VERSION 5.8 ;
BUSBITCHARS "[]" ;
DIVIDERCHAR "/" ;
UNITS
    DATABASE MICRONS 2000 ;
END UNITS

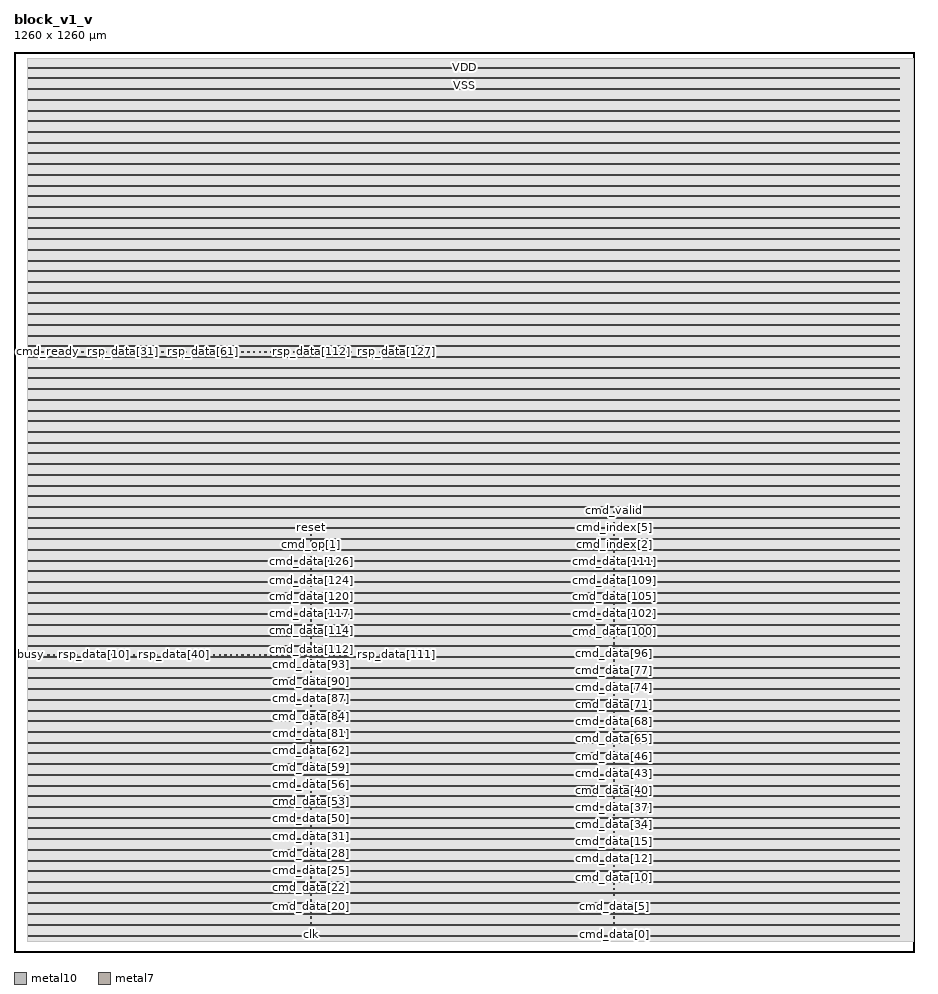
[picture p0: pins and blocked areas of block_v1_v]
MACRO block_v1_v
  FOREIGN block_v1_v 0 0 ;
  CLASS BLOCK ;
  SIZE 1260 BY 1260 ;
  PIN busy
    DIRECTION OUTPUT ;
    USE SIGNAL ;
    PORT
      LAYER metal10 ;
        RECT  23.095 415.07 25.095 417.07 ;
    END
  END busy
  PIN clk
    DIRECTION INPUT ;
    USE SIGNAL ;
    PORT
      LAYER metal10 ;
        RECT  415.095 23.07 417.095 25.07 ;
    END
  END clk
  PIN cmd_data[0]
    DIRECTION INPUT ;
    USE SIGNAL ;
    PORT
      LAYER metal10 ;
        RECT  839.095 23.07 841.095 25.07 ;
    END
  END cmd_data[0]
  PIN cmd_data[100]
    DIRECTION INPUT ;
    USE SIGNAL ;
    PORT
      LAYER metal10 ;
        RECT  839.095 447.07 841.095 449.07 ;
    END
  END cmd_data[100]
  PIN cmd_data[101]
    DIRECTION INPUT ;
    USE SIGNAL ;
    PORT
      LAYER metal10 ;
        RECT  839.095 455.07 841.095 457.07 ;
    END
  END cmd_data[101]
  PIN cmd_data[102]
    DIRECTION INPUT ;
    USE SIGNAL ;
    PORT
      LAYER metal10 ;
        RECT  839.095 463.07 841.095 465.07 ;
    END
  END cmd_data[102]
  PIN cmd_data[103]
    DIRECTION INPUT ;
    USE SIGNAL ;
    PORT
      LAYER metal10 ;
        RECT  839.095 471.07 841.095 473.07 ;
    END
  END cmd_data[103]
  PIN cmd_data[104]
    DIRECTION INPUT ;
    USE SIGNAL ;
    PORT
      LAYER metal10 ;
        RECT  839.095 479.07 841.095 481.07 ;
    END
  END cmd_data[104]
  PIN cmd_data[105]
    DIRECTION INPUT ;
    USE SIGNAL ;
    PORT
      LAYER metal10 ;
        RECT  839.095 487.07 841.095 489.07 ;
    END
  END cmd_data[105]
  PIN cmd_data[106]
    DIRECTION INPUT ;
    USE SIGNAL ;
    PORT
      LAYER metal10 ;
        RECT  839.095 495.07 841.095 497.07 ;
    END
  END cmd_data[106]
  PIN cmd_data[107]
    DIRECTION INPUT ;
    USE SIGNAL ;
    PORT
      LAYER metal10 ;
        RECT  839.095 503.07 841.095 505.07 ;
    END
  END cmd_data[107]
  PIN cmd_data[108]
    DIRECTION INPUT ;
    USE SIGNAL ;
    PORT
      LAYER metal10 ;
        RECT  839.095 511.07 841.095 513.07 ;
    END
  END cmd_data[108]
  PIN cmd_data[109]
    DIRECTION INPUT ;
    USE SIGNAL ;
    PORT
      LAYER metal10 ;
        RECT  839.095 519.07 841.095 521.07 ;
    END
  END cmd_data[109]
  PIN cmd_data[10]
    DIRECTION INPUT ;
    USE SIGNAL ;
    PORT
      LAYER metal10 ;
        RECT  839.095 103.07 841.095 105.07 ;
    END
  END cmd_data[10]
  PIN cmd_data[110]
    DIRECTION INPUT ;
    USE SIGNAL ;
    PORT
      LAYER metal10 ;
        RECT  839.095 527.07 841.095 529.07 ;
    END
  END cmd_data[110]
  PIN cmd_data[111]
    DIRECTION INPUT ;
    USE SIGNAL ;
    PORT
      LAYER metal10 ;
        RECT  839.095 535.07 841.095 537.07 ;
    END
  END cmd_data[111]
  PIN cmd_data[112]
    DIRECTION INPUT ;
    USE SIGNAL ;
    PORT
      LAYER metal10 ;
        RECT  415.095 423.07 417.095 425.07 ;
    END
  END cmd_data[112]
  PIN cmd_data[113]
    DIRECTION INPUT ;
    USE SIGNAL ;
    PORT
      LAYER metal10 ;
        RECT  415.095 431.07 417.095 433.07 ;
    END
  END cmd_data[113]
  PIN cmd_data[114]
    DIRECTION INPUT ;
    USE SIGNAL ;
    PORT
      LAYER metal10 ;
        RECT  415.095 439.07 417.095 441.07 ;
    END
  END cmd_data[114]
  PIN cmd_data[115]
    DIRECTION INPUT ;
    USE SIGNAL ;
    PORT
      LAYER metal10 ;
        RECT  415.095 447.07 417.095 449.07 ;
    END
  END cmd_data[115]
  PIN cmd_data[116]
    DIRECTION INPUT ;
    USE SIGNAL ;
    PORT
      LAYER metal10 ;
        RECT  415.095 455.07 417.095 457.07 ;
    END
  END cmd_data[116]
  PIN cmd_data[117]
    DIRECTION INPUT ;
    USE SIGNAL ;
    PORT
      LAYER metal10 ;
        RECT  415.095 463.07 417.095 465.07 ;
    END
  END cmd_data[117]
  PIN cmd_data[118]
    DIRECTION INPUT ;
    USE SIGNAL ;
    PORT
      LAYER metal10 ;
        RECT  415.095 471.07 417.095 473.07 ;
    END
  END cmd_data[118]
  PIN cmd_data[119]
    DIRECTION INPUT ;
    USE SIGNAL ;
    PORT
      LAYER metal10 ;
        RECT  415.095 479.07 417.095 481.07 ;
    END
  END cmd_data[119]
  PIN cmd_data[11]
    DIRECTION INPUT ;
    USE SIGNAL ;
    PORT
      LAYER metal10 ;
        RECT  839.095 111.07 841.095 113.07 ;
    END
  END cmd_data[11]
  PIN cmd_data[120]
    DIRECTION INPUT ;
    USE SIGNAL ;
    PORT
      LAYER metal10 ;
        RECT  415.095 487.07 417.095 489.07 ;
    END
  END cmd_data[120]
  PIN cmd_data[121]
    DIRECTION INPUT ;
    USE SIGNAL ;
    PORT
      LAYER metal10 ;
        RECT  415.095 495.07 417.095 497.07 ;
    END
  END cmd_data[121]
  PIN cmd_data[122]
    DIRECTION INPUT ;
    USE SIGNAL ;
    PORT
      LAYER metal10 ;
        RECT  415.095 503.07 417.095 505.07 ;
    END
  END cmd_data[122]
  PIN cmd_data[123]
    DIRECTION INPUT ;
    USE SIGNAL ;
    PORT
      LAYER metal10 ;
        RECT  415.095 511.07 417.095 513.07 ;
    END
  END cmd_data[123]
  PIN cmd_data[124]
    DIRECTION INPUT ;
    USE SIGNAL ;
    PORT
      LAYER metal10 ;
        RECT  415.095 519.07 417.095 521.07 ;
    END
  END cmd_data[124]
  PIN cmd_data[125]
    DIRECTION INPUT ;
    USE SIGNAL ;
    PORT
      LAYER metal10 ;
        RECT  415.095 527.07 417.095 529.07 ;
    END
  END cmd_data[125]
  PIN cmd_data[126]
    DIRECTION INPUT ;
    USE SIGNAL ;
    PORT
      LAYER metal10 ;
        RECT  415.095 535.07 417.095 537.07 ;
    END
  END cmd_data[126]
  PIN cmd_data[127]
    DIRECTION INPUT ;
    USE SIGNAL ;
    PORT
      LAYER metal10 ;
        RECT  415.095 543.07 417.095 545.07 ;
    END
  END cmd_data[127]
  PIN cmd_data[12]
    DIRECTION INPUT ;
    USE SIGNAL ;
    PORT
      LAYER metal10 ;
        RECT  839.095 119.07 841.095 121.07 ;
    END
  END cmd_data[12]
  PIN cmd_data[13]
    DIRECTION INPUT ;
    USE SIGNAL ;
    PORT
      LAYER metal10 ;
        RECT  839.095 127.07 841.095 129.07 ;
    END
  END cmd_data[13]
  PIN cmd_data[14]
    DIRECTION INPUT ;
    USE SIGNAL ;
    PORT
      LAYER metal10 ;
        RECT  839.095 135.07 841.095 137.07 ;
    END
  END cmd_data[14]
  PIN cmd_data[15]
    DIRECTION INPUT ;
    USE SIGNAL ;
    PORT
      LAYER metal10 ;
        RECT  839.095 143.07 841.095 145.07 ;
    END
  END cmd_data[15]
  PIN cmd_data[16]
    DIRECTION INPUT ;
    USE SIGNAL ;
    PORT
      LAYER metal10 ;
        RECT  415.095 31.07 417.095 33.07 ;
    END
  END cmd_data[16]
  PIN cmd_data[17]
    DIRECTION INPUT ;
    USE SIGNAL ;
    PORT
      LAYER metal10 ;
        RECT  415.095 39.07 417.095 41.07 ;
    END
  END cmd_data[17]
  PIN cmd_data[18]
    DIRECTION INPUT ;
    USE SIGNAL ;
    PORT
      LAYER metal10 ;
        RECT  415.095 47.07 417.095 49.07 ;
    END
  END cmd_data[18]
  PIN cmd_data[19]
    DIRECTION INPUT ;
    USE SIGNAL ;
    PORT
      LAYER metal10 ;
        RECT  415.095 55.07 417.095 57.07 ;
    END
  END cmd_data[19]
  PIN cmd_data[1]
    DIRECTION INPUT ;
    USE SIGNAL ;
    PORT
      LAYER metal10 ;
        RECT  839.095 31.07 841.095 33.07 ;
    END
  END cmd_data[1]
  PIN cmd_data[20]
    DIRECTION INPUT ;
    USE SIGNAL ;
    PORT
      LAYER metal10 ;
        RECT  415.095 63.07 417.095 65.07 ;
    END
  END cmd_data[20]
  PIN cmd_data[21]
    DIRECTION INPUT ;
    USE SIGNAL ;
    PORT
      LAYER metal10 ;
        RECT  415.095 71.07 417.095 73.07 ;
    END
  END cmd_data[21]
  PIN cmd_data[22]
    DIRECTION INPUT ;
    USE SIGNAL ;
    PORT
      LAYER metal10 ;
        RECT  415.095 79.07 417.095 81.07 ;
    END
  END cmd_data[22]
  PIN cmd_data[23]
    DIRECTION INPUT ;
    USE SIGNAL ;
    PORT
      LAYER metal10 ;
        RECT  415.095 87.07 417.095 89.07 ;
    END
  END cmd_data[23]
  PIN cmd_data[24]
    DIRECTION INPUT ;
    USE SIGNAL ;
    PORT
      LAYER metal10 ;
        RECT  415.095 95.07 417.095 97.07 ;
    END
  END cmd_data[24]
  PIN cmd_data[25]
    DIRECTION INPUT ;
    USE SIGNAL ;
    PORT
      LAYER metal10 ;
        RECT  415.095 103.07 417.095 105.07 ;
    END
  END cmd_data[25]
  PIN cmd_data[26]
    DIRECTION INPUT ;
    USE SIGNAL ;
    PORT
      LAYER metal10 ;
        RECT  415.095 111.07 417.095 113.07 ;
    END
  END cmd_data[26]
  PIN cmd_data[27]
    DIRECTION INPUT ;
    USE SIGNAL ;
    PORT
      LAYER metal10 ;
        RECT  415.095 119.07 417.095 121.07 ;
    END
  END cmd_data[27]
  PIN cmd_data[28]
    DIRECTION INPUT ;
    USE SIGNAL ;
    PORT
      LAYER metal10 ;
        RECT  415.095 127.07 417.095 129.07 ;
    END
  END cmd_data[28]
  PIN cmd_data[29]
    DIRECTION INPUT ;
    USE SIGNAL ;
    PORT
      LAYER metal10 ;
        RECT  415.095 135.07 417.095 137.07 ;
    END
  END cmd_data[29]
  PIN cmd_data[2]
    DIRECTION INPUT ;
    USE SIGNAL ;
    PORT
      LAYER metal10 ;
        RECT  839.095 39.07 841.095 41.07 ;
    END
  END cmd_data[2]
  PIN cmd_data[30]
    DIRECTION INPUT ;
    USE SIGNAL ;
    PORT
      LAYER metal10 ;
        RECT  415.095 143.07 417.095 145.07 ;
    END
  END cmd_data[30]
  PIN cmd_data[31]
    DIRECTION INPUT ;
    USE SIGNAL ;
    PORT
      LAYER metal10 ;
        RECT  415.095 151.07 417.095 153.07 ;
    END
  END cmd_data[31]
  PIN cmd_data[32]
    DIRECTION INPUT ;
    USE SIGNAL ;
    PORT
      LAYER metal10 ;
        RECT  839.095 151.07 841.095 153.07 ;
    END
  END cmd_data[32]
  PIN cmd_data[33]
    DIRECTION INPUT ;
    USE SIGNAL ;
    PORT
      LAYER metal10 ;
        RECT  839.095 159.07 841.095 161.07 ;
    END
  END cmd_data[33]
  PIN cmd_data[34]
    DIRECTION INPUT ;
    USE SIGNAL ;
    PORT
      LAYER metal10 ;
        RECT  839.095 167.07 841.095 169.07 ;
    END
  END cmd_data[34]
  PIN cmd_data[35]
    DIRECTION INPUT ;
    USE SIGNAL ;
    PORT
      LAYER metal10 ;
        RECT  839.095 175.07 841.095 177.07 ;
    END
  END cmd_data[35]
  PIN cmd_data[36]
    DIRECTION INPUT ;
    USE SIGNAL ;
    PORT
      LAYER metal10 ;
        RECT  839.095 183.07 841.095 185.07 ;
    END
  END cmd_data[36]
  PIN cmd_data[37]
    DIRECTION INPUT ;
    USE SIGNAL ;
    PORT
      LAYER metal10 ;
        RECT  839.095 191.07 841.095 193.07 ;
    END
  END cmd_data[37]
  PIN cmd_data[38]
    DIRECTION INPUT ;
    USE SIGNAL ;
    PORT
      LAYER metal10 ;
        RECT  839.095 199.07 841.095 201.07 ;
    END
  END cmd_data[38]
  PIN cmd_data[39]
    DIRECTION INPUT ;
    USE SIGNAL ;
    PORT
      LAYER metal10 ;
        RECT  839.095 207.07 841.095 209.07 ;
    END
  END cmd_data[39]
  PIN cmd_data[3]
    DIRECTION INPUT ;
    USE SIGNAL ;
    PORT
      LAYER metal10 ;
        RECT  839.095 47.07 841.095 49.07 ;
    END
  END cmd_data[3]
  PIN cmd_data[40]
    DIRECTION INPUT ;
    USE SIGNAL ;
    PORT
      LAYER metal10 ;
        RECT  839.095 215.07 841.095 217.07 ;
    END
  END cmd_data[40]
  PIN cmd_data[41]
    DIRECTION INPUT ;
    USE SIGNAL ;
    PORT
      LAYER metal10 ;
        RECT  839.095 223.07 841.095 225.07 ;
    END
  END cmd_data[41]
  PIN cmd_data[42]
    DIRECTION INPUT ;
    USE SIGNAL ;
    PORT
      LAYER metal10 ;
        RECT  839.095 231.07 841.095 233.07 ;
    END
  END cmd_data[42]
  PIN cmd_data[43]
    DIRECTION INPUT ;
    USE SIGNAL ;
    PORT
      LAYER metal10 ;
        RECT  839.095 239.07 841.095 241.07 ;
    END
  END cmd_data[43]
  PIN cmd_data[44]
    DIRECTION INPUT ;
    USE SIGNAL ;
    PORT
      LAYER metal10 ;
        RECT  839.095 247.07 841.095 249.07 ;
    END
  END cmd_data[44]
  PIN cmd_data[45]
    DIRECTION INPUT ;
    USE SIGNAL ;
    PORT
      LAYER metal10 ;
        RECT  839.095 255.07 841.095 257.07 ;
    END
  END cmd_data[45]
  PIN cmd_data[46]
    DIRECTION INPUT ;
    USE SIGNAL ;
    PORT
      LAYER metal10 ;
        RECT  839.095 263.07 841.095 265.07 ;
    END
  END cmd_data[46]
  PIN cmd_data[47]
    DIRECTION INPUT ;
    USE SIGNAL ;
    PORT
      LAYER metal10 ;
        RECT  839.095 271.07 841.095 273.07 ;
    END
  END cmd_data[47]
  PIN cmd_data[48]
    DIRECTION INPUT ;
    USE SIGNAL ;
    PORT
      LAYER metal10 ;
        RECT  415.095 159.07 417.095 161.07 ;
    END
  END cmd_data[48]
  PIN cmd_data[49]
    DIRECTION INPUT ;
    USE SIGNAL ;
    PORT
      LAYER metal10 ;
        RECT  415.095 167.07 417.095 169.07 ;
    END
  END cmd_data[49]
  PIN cmd_data[4]
    DIRECTION INPUT ;
    USE SIGNAL ;
    PORT
      LAYER metal10 ;
        RECT  839.095 55.07 841.095 57.07 ;
    END
  END cmd_data[4]
  PIN cmd_data[50]
    DIRECTION INPUT ;
    USE SIGNAL ;
    PORT
      LAYER metal10 ;
        RECT  415.095 175.07 417.095 177.07 ;
    END
  END cmd_data[50]
  PIN cmd_data[51]
    DIRECTION INPUT ;
    USE SIGNAL ;
    PORT
      LAYER metal10 ;
        RECT  415.095 183.07 417.095 185.07 ;
    END
  END cmd_data[51]
  PIN cmd_data[52]
    DIRECTION INPUT ;
    USE SIGNAL ;
    PORT
      LAYER metal10 ;
        RECT  415.095 191.07 417.095 193.07 ;
    END
  END cmd_data[52]
  PIN cmd_data[53]
    DIRECTION INPUT ;
    USE SIGNAL ;
    PORT
      LAYER metal10 ;
        RECT  415.095 199.07 417.095 201.07 ;
    END
  END cmd_data[53]
  PIN cmd_data[54]
    DIRECTION INPUT ;
    USE SIGNAL ;
    PORT
      LAYER metal10 ;
        RECT  415.095 207.07 417.095 209.07 ;
    END
  END cmd_data[54]
  PIN cmd_data[55]
    DIRECTION INPUT ;
    USE SIGNAL ;
    PORT
      LAYER metal10 ;
        RECT  415.095 215.07 417.095 217.07 ;
    END
  END cmd_data[55]
  PIN cmd_data[56]
    DIRECTION INPUT ;
    USE SIGNAL ;
    PORT
      LAYER metal10 ;
        RECT  415.095 223.07 417.095 225.07 ;
    END
  END cmd_data[56]
  PIN cmd_data[57]
    DIRECTION INPUT ;
    USE SIGNAL ;
    PORT
      LAYER metal10 ;
        RECT  415.095 231.07 417.095 233.07 ;
    END
  END cmd_data[57]
  PIN cmd_data[58]
    DIRECTION INPUT ;
    USE SIGNAL ;
    PORT
      LAYER metal10 ;
        RECT  415.095 239.07 417.095 241.07 ;
    END
  END cmd_data[58]
  PIN cmd_data[59]
    DIRECTION INPUT ;
    USE SIGNAL ;
    PORT
      LAYER metal10 ;
        RECT  415.095 247.07 417.095 249.07 ;
    END
  END cmd_data[59]
  PIN cmd_data[5]
    DIRECTION INPUT ;
    USE SIGNAL ;
    PORT
      LAYER metal10 ;
        RECT  839.095 63.07 841.095 65.07 ;
    END
  END cmd_data[5]
  PIN cmd_data[60]
    DIRECTION INPUT ;
    USE SIGNAL ;
    PORT
      LAYER metal10 ;
        RECT  415.095 255.07 417.095 257.07 ;
    END
  END cmd_data[60]
  PIN cmd_data[61]
    DIRECTION INPUT ;
    USE SIGNAL ;
    PORT
      LAYER metal10 ;
        RECT  415.095 263.07 417.095 265.07 ;
    END
  END cmd_data[61]
  PIN cmd_data[62]
    DIRECTION INPUT ;
    USE SIGNAL ;
    PORT
      LAYER metal10 ;
        RECT  415.095 271.07 417.095 273.07 ;
    END
  END cmd_data[62]
  PIN cmd_data[63]
    DIRECTION INPUT ;
    USE SIGNAL ;
    PORT
      LAYER metal10 ;
        RECT  415.095 279.07 417.095 281.07 ;
    END
  END cmd_data[63]
  PIN cmd_data[64]
    DIRECTION INPUT ;
    USE SIGNAL ;
    PORT
      LAYER metal10 ;
        RECT  839.095 279.07 841.095 281.07 ;
    END
  END cmd_data[64]
  PIN cmd_data[65]
    DIRECTION INPUT ;
    USE SIGNAL ;
    PORT
      LAYER metal10 ;
        RECT  839.095 287.07 841.095 289.07 ;
    END
  END cmd_data[65]
  PIN cmd_data[66]
    DIRECTION INPUT ;
    USE SIGNAL ;
    PORT
      LAYER metal10 ;
        RECT  839.095 295.07 841.095 297.07 ;
    END
  END cmd_data[66]
  PIN cmd_data[67]
    DIRECTION INPUT ;
    USE SIGNAL ;
    PORT
      LAYER metal10 ;
        RECT  839.095 303.07 841.095 305.07 ;
    END
  END cmd_data[67]
  PIN cmd_data[68]
    DIRECTION INPUT ;
    USE SIGNAL ;
    PORT
      LAYER metal10 ;
        RECT  839.095 311.07 841.095 313.07 ;
    END
  END cmd_data[68]
  PIN cmd_data[69]
    DIRECTION INPUT ;
    USE SIGNAL ;
    PORT
      LAYER metal10 ;
        RECT  839.095 319.07 841.095 321.07 ;
    END
  END cmd_data[69]
  PIN cmd_data[6]
    DIRECTION INPUT ;
    USE SIGNAL ;
    PORT
      LAYER metal10 ;
        RECT  839.095 71.07 841.095 73.07 ;
    END
  END cmd_data[6]
  PIN cmd_data[70]
    DIRECTION INPUT ;
    USE SIGNAL ;
    PORT
      LAYER metal10 ;
        RECT  839.095 327.07 841.095 329.07 ;
    END
  END cmd_data[70]
  PIN cmd_data[71]
    DIRECTION INPUT ;
    USE SIGNAL ;
    PORT
      LAYER metal10 ;
        RECT  839.095 335.07 841.095 337.07 ;
    END
  END cmd_data[71]
  PIN cmd_data[72]
    DIRECTION INPUT ;
    USE SIGNAL ;
    PORT
      LAYER metal10 ;
        RECT  839.095 343.07 841.095 345.07 ;
    END
  END cmd_data[72]
  PIN cmd_data[73]
    DIRECTION INPUT ;
    USE SIGNAL ;
    PORT
      LAYER metal10 ;
        RECT  839.095 351.07 841.095 353.07 ;
    END
  END cmd_data[73]
  PIN cmd_data[74]
    DIRECTION INPUT ;
    USE SIGNAL ;
    PORT
      LAYER metal10 ;
        RECT  839.095 359.07 841.095 361.07 ;
    END
  END cmd_data[74]
  PIN cmd_data[75]
    DIRECTION INPUT ;
    USE SIGNAL ;
    PORT
      LAYER metal10 ;
        RECT  839.095 367.07 841.095 369.07 ;
    END
  END cmd_data[75]
  PIN cmd_data[76]
    DIRECTION INPUT ;
    USE SIGNAL ;
    PORT
      LAYER metal10 ;
        RECT  839.095 375.07 841.095 377.07 ;
    END
  END cmd_data[76]
  PIN cmd_data[77]
    DIRECTION INPUT ;
    USE SIGNAL ;
    PORT
      LAYER metal10 ;
        RECT  839.095 383.07 841.095 385.07 ;
    END
  END cmd_data[77]
  PIN cmd_data[78]
    DIRECTION INPUT ;
    USE SIGNAL ;
    PORT
      LAYER metal10 ;
        RECT  839.095 391.07 841.095 393.07 ;
    END
  END cmd_data[78]
  PIN cmd_data[79]
    DIRECTION INPUT ;
    USE SIGNAL ;
    PORT
      LAYER metal10 ;
        RECT  839.095 399.07 841.095 401.07 ;
    END
  END cmd_data[79]
  PIN cmd_data[7]
    DIRECTION INPUT ;
    USE SIGNAL ;
    PORT
      LAYER metal10 ;
        RECT  839.095 79.07 841.095 81.07 ;
    END
  END cmd_data[7]
  PIN cmd_data[80]
    DIRECTION INPUT ;
    USE SIGNAL ;
    PORT
      LAYER metal10 ;
        RECT  415.095 287.07 417.095 289.07 ;
    END
  END cmd_data[80]
  PIN cmd_data[81]
    DIRECTION INPUT ;
    USE SIGNAL ;
    PORT
      LAYER metal10 ;
        RECT  415.095 295.07 417.095 297.07 ;
    END
  END cmd_data[81]
  PIN cmd_data[82]
    DIRECTION INPUT ;
    USE SIGNAL ;
    PORT
      LAYER metal10 ;
        RECT  415.095 303.07 417.095 305.07 ;
    END
  END cmd_data[82]
  PIN cmd_data[83]
    DIRECTION INPUT ;
    USE SIGNAL ;
    PORT
      LAYER metal10 ;
        RECT  415.095 311.07 417.095 313.07 ;
    END
  END cmd_data[83]
  PIN cmd_data[84]
    DIRECTION INPUT ;
    USE SIGNAL ;
    PORT
      LAYER metal10 ;
        RECT  415.095 319.07 417.095 321.07 ;
    END
  END cmd_data[84]
  PIN cmd_data[85]
    DIRECTION INPUT ;
    USE SIGNAL ;
    PORT
      LAYER metal10 ;
        RECT  415.095 327.07 417.095 329.07 ;
    END
  END cmd_data[85]
  PIN cmd_data[86]
    DIRECTION INPUT ;
    USE SIGNAL ;
    PORT
      LAYER metal10 ;
        RECT  415.095 335.07 417.095 337.07 ;
    END
  END cmd_data[86]
  PIN cmd_data[87]
    DIRECTION INPUT ;
    USE SIGNAL ;
    PORT
      LAYER metal10 ;
        RECT  415.095 343.07 417.095 345.07 ;
    END
  END cmd_data[87]
  PIN cmd_data[88]
    DIRECTION INPUT ;
    USE SIGNAL ;
    PORT
      LAYER metal10 ;
        RECT  415.095 351.07 417.095 353.07 ;
    END
  END cmd_data[88]
  PIN cmd_data[89]
    DIRECTION INPUT ;
    USE SIGNAL ;
    PORT
      LAYER metal10 ;
        RECT  415.095 359.07 417.095 361.07 ;
    END
  END cmd_data[89]
  PIN cmd_data[8]
    DIRECTION INPUT ;
    USE SIGNAL ;
    PORT
      LAYER metal10 ;
        RECT  839.095 87.07 841.095 89.07 ;
    END
  END cmd_data[8]
  PIN cmd_data[90]
    DIRECTION INPUT ;
    USE SIGNAL ;
    PORT
      LAYER metal10 ;
        RECT  415.095 367.07 417.095 369.07 ;
    END
  END cmd_data[90]
  PIN cmd_data[91]
    DIRECTION INPUT ;
    USE SIGNAL ;
    PORT
      LAYER metal10 ;
        RECT  415.095 375.07 417.095 377.07 ;
    END
  END cmd_data[91]
  PIN cmd_data[92]
    DIRECTION INPUT ;
    USE SIGNAL ;
    PORT
      LAYER metal10 ;
        RECT  415.095 383.07 417.095 385.07 ;
    END
  END cmd_data[92]
  PIN cmd_data[93]
    DIRECTION INPUT ;
    USE SIGNAL ;
    PORT
      LAYER metal10 ;
        RECT  415.095 391.07 417.095 393.07 ;
    END
  END cmd_data[93]
  PIN cmd_data[94]
    DIRECTION INPUT ;
    USE SIGNAL ;
    PORT
      LAYER metal10 ;
        RECT  415.095 399.07 417.095 401.07 ;
    END
  END cmd_data[94]
  PIN cmd_data[95]
    DIRECTION INPUT ;
    USE SIGNAL ;
    PORT
      LAYER metal10 ;
        RECT  415.095 407.07 417.095 409.07 ;
    END
  END cmd_data[95]
  PIN cmd_data[96]
    DIRECTION INPUT ;
    USE SIGNAL ;
    PORT
      LAYER metal10 ;
        RECT  839.095 407.07 841.095 409.07 ;
    END
  END cmd_data[96]
  PIN cmd_data[97]
    DIRECTION INPUT ;
    USE SIGNAL ;
    PORT
      LAYER metal10 ;
        RECT  839.095 423.07 841.095 425.07 ;
    END
  END cmd_data[97]
  PIN cmd_data[98]
    DIRECTION INPUT ;
    USE SIGNAL ;
    PORT
      LAYER metal10 ;
        RECT  839.095 431.07 841.095 433.07 ;
    END
  END cmd_data[98]
  PIN cmd_data[99]
    DIRECTION INPUT ;
    USE SIGNAL ;
    PORT
      LAYER metal10 ;
        RECT  839.095 439.07 841.095 441.07 ;
    END
  END cmd_data[99]
  PIN cmd_data[9]
    DIRECTION INPUT ;
    USE SIGNAL ;
    PORT
      LAYER metal10 ;
        RECT  839.095 95.07 841.095 97.07 ;
    END
  END cmd_data[9]
  PIN cmd_index[0]
    DIRECTION INPUT ;
    USE SIGNAL ;
    PORT
      LAYER metal10 ;
        RECT  839.095 543.07 841.095 545.07 ;
    END
  END cmd_index[0]
  PIN cmd_index[1]
    DIRECTION INPUT ;
    USE SIGNAL ;
    PORT
      LAYER metal10 ;
        RECT  839.095 551.07 841.095 553.07 ;
    END
  END cmd_index[1]
  PIN cmd_index[2]
    DIRECTION INPUT ;
    USE SIGNAL ;
    PORT
      LAYER metal10 ;
        RECT  839.095 559.07 841.095 561.07 ;
    END
  END cmd_index[2]
  PIN cmd_index[3]
    DIRECTION INPUT ;
    USE SIGNAL ;
    PORT
      LAYER metal10 ;
        RECT  839.095 567.07 841.095 569.07 ;
    END
  END cmd_index[3]
  PIN cmd_index[4]
    DIRECTION INPUT ;
    USE SIGNAL ;
    PORT
      LAYER metal10 ;
        RECT  839.095 575.07 841.095 577.07 ;
    END
  END cmd_index[4]
  PIN cmd_index[5]
    DIRECTION INPUT ;
    USE SIGNAL ;
    PORT
      LAYER metal10 ;
        RECT  839.095 583.07 841.095 585.07 ;
    END
  END cmd_index[5]
  PIN cmd_index[6]
    DIRECTION INPUT ;
    USE SIGNAL ;
    PORT
      LAYER metal10 ;
        RECT  839.095 591.07 841.095 593.07 ;
    END
  END cmd_index[6]
  PIN cmd_index[7]
    DIRECTION INPUT ;
    USE SIGNAL ;
    PORT
      LAYER metal10 ;
        RECT  839.095 599.07 841.095 601.07 ;
    END
  END cmd_index[7]
  PIN cmd_op[0]
    DIRECTION INPUT ;
    USE SIGNAL ;
    PORT
      LAYER metal10 ;
        RECT  415.095 551.07 417.095 553.07 ;
    END
  END cmd_op[0]
  PIN cmd_op[1]
    DIRECTION INPUT ;
    USE SIGNAL ;
    PORT
      LAYER metal10 ;
        RECT  415.095 559.07 417.095 561.07 ;
    END
  END cmd_op[1]
  PIN cmd_op[2]
    DIRECTION INPUT ;
    USE SIGNAL ;
    PORT
      LAYER metal10 ;
        RECT  415.095 567.07 417.095 569.07 ;
    END
  END cmd_op[2]
  PIN cmd_op[3]
    DIRECTION INPUT ;
    USE SIGNAL ;
    PORT
      LAYER metal10 ;
        RECT  415.095 575.07 417.095 577.07 ;
    END
  END cmd_op[3]
  PIN cmd_ready
    DIRECTION OUTPUT ;
    USE SIGNAL ;
    PORT
      LAYER metal10 ;
        RECT  23.095 839.07 25.095 841.07 ;
    END
  END cmd_ready
  PIN cmd_valid
    DIRECTION INPUT ;
    USE SIGNAL ;
    PORT
      LAYER metal10 ;
        RECT  839.095 607.07 841.095 609.07 ;
    END
  END cmd_valid
  PIN reset
    DIRECTION INPUT ;
    USE SIGNAL ;
    PORT
      LAYER metal10 ;
        RECT  415.095 583.07 417.095 585.07 ;
    END
  END reset
  PIN rsp_data[0]
    DIRECTION OUTPUT ;
    USE SIGNAL ;
    PORT
      LAYER metal10 ;
        RECT  31.095 415.07 33.095 417.07 ;
    END
  END rsp_data[0]
  PIN rsp_data[100]
    DIRECTION OUTPUT ;
    USE SIGNAL ;
    PORT
      LAYER metal10 ;
        RECT  447.095 415.07 449.095 417.07 ;
    END
  END rsp_data[100]
  PIN rsp_data[101]
    DIRECTION OUTPUT ;
    USE SIGNAL ;
    PORT
      LAYER metal10 ;
        RECT  455.095 415.07 457.095 417.07 ;
    END
  END rsp_data[101]
  PIN rsp_data[102]
    DIRECTION OUTPUT ;
    USE SIGNAL ;
    PORT
      LAYER metal10 ;
        RECT  463.095 415.07 465.095 417.07 ;
    END
  END rsp_data[102]
  PIN rsp_data[103]
    DIRECTION OUTPUT ;
    USE SIGNAL ;
    PORT
      LAYER metal10 ;
        RECT  471.095 415.07 473.095 417.07 ;
    END
  END rsp_data[103]
  PIN rsp_data[104]
    DIRECTION OUTPUT ;
    USE SIGNAL ;
    PORT
      LAYER metal10 ;
        RECT  479.095 415.07 481.095 417.07 ;
    END
  END rsp_data[104]
  PIN rsp_data[105]
    DIRECTION OUTPUT ;
    USE SIGNAL ;
    PORT
      LAYER metal10 ;
        RECT  487.095 415.07 489.095 417.07 ;
    END
  END rsp_data[105]
  PIN rsp_data[106]
    DIRECTION OUTPUT ;
    USE SIGNAL ;
    PORT
      LAYER metal10 ;
        RECT  495.095 415.07 497.095 417.07 ;
    END
  END rsp_data[106]
  PIN rsp_data[107]
    DIRECTION OUTPUT ;
    USE SIGNAL ;
    PORT
      LAYER metal10 ;
        RECT  503.095 415.07 505.095 417.07 ;
    END
  END rsp_data[107]
  PIN rsp_data[108]
    DIRECTION OUTPUT ;
    USE SIGNAL ;
    PORT
      LAYER metal10 ;
        RECT  511.095 415.07 513.095 417.07 ;
    END
  END rsp_data[108]
  PIN rsp_data[109]
    DIRECTION OUTPUT ;
    USE SIGNAL ;
    PORT
      LAYER metal10 ;
        RECT  519.095 415.07 521.095 417.07 ;
    END
  END rsp_data[109]
  PIN rsp_data[10]
    DIRECTION OUTPUT ;
    USE SIGNAL ;
    PORT
      LAYER metal10 ;
        RECT  111.095 415.07 113.095 417.07 ;
    END
  END rsp_data[10]
  PIN rsp_data[110]
    DIRECTION OUTPUT ;
    USE SIGNAL ;
    PORT
      LAYER metal10 ;
        RECT  527.095 415.07 529.095 417.07 ;
    END
  END rsp_data[110]
  PIN rsp_data[111]
    DIRECTION OUTPUT ;
    USE SIGNAL ;
    PORT
      LAYER metal10 ;
        RECT  535.095 415.07 537.095 417.07 ;
    END
  END rsp_data[111]
  PIN rsp_data[112]
    DIRECTION OUTPUT ;
    USE SIGNAL ;
    PORT
      LAYER metal10 ;
        RECT  415.095 839.07 417.095 841.07 ;
    END
  END rsp_data[112]
  PIN rsp_data[113]
    DIRECTION OUTPUT ;
    USE SIGNAL ;
    PORT
      LAYER metal10 ;
        RECT  423.095 839.07 425.095 841.07 ;
    END
  END rsp_data[113]
  PIN rsp_data[114]
    DIRECTION OUTPUT ;
    USE SIGNAL ;
    PORT
      LAYER metal10 ;
        RECT  431.095 839.07 433.095 841.07 ;
    END
  END rsp_data[114]
  PIN rsp_data[115]
    DIRECTION OUTPUT ;
    USE SIGNAL ;
    PORT
      LAYER metal10 ;
        RECT  439.095 839.07 441.095 841.07 ;
    END
  END rsp_data[115]
  PIN rsp_data[116]
    DIRECTION OUTPUT ;
    USE SIGNAL ;
    PORT
      LAYER metal10 ;
        RECT  447.095 839.07 449.095 841.07 ;
    END
  END rsp_data[116]
  PIN rsp_data[117]
    DIRECTION OUTPUT ;
    USE SIGNAL ;
    PORT
      LAYER metal10 ;
        RECT  455.095 839.07 457.095 841.07 ;
    END
  END rsp_data[117]
  PIN rsp_data[118]
    DIRECTION OUTPUT ;
    USE SIGNAL ;
    PORT
      LAYER metal10 ;
        RECT  463.095 839.07 465.095 841.07 ;
    END
  END rsp_data[118]
  PIN rsp_data[119]
    DIRECTION OUTPUT ;
    USE SIGNAL ;
    PORT
      LAYER metal10 ;
        RECT  471.095 839.07 473.095 841.07 ;
    END
  END rsp_data[119]
  PIN rsp_data[11]
    DIRECTION OUTPUT ;
    USE SIGNAL ;
    PORT
      LAYER metal10 ;
        RECT  119.095 415.07 121.095 417.07 ;
    END
  END rsp_data[11]
  PIN rsp_data[120]
    DIRECTION OUTPUT ;
    USE SIGNAL ;
    PORT
      LAYER metal10 ;
        RECT  479.095 839.07 481.095 841.07 ;
    END
  END rsp_data[120]
  PIN rsp_data[121]
    DIRECTION OUTPUT ;
    USE SIGNAL ;
    PORT
      LAYER metal10 ;
        RECT  487.095 839.07 489.095 841.07 ;
    END
  END rsp_data[121]
  PIN rsp_data[122]
    DIRECTION OUTPUT ;
    USE SIGNAL ;
    PORT
      LAYER metal10 ;
        RECT  495.095 839.07 497.095 841.07 ;
    END
  END rsp_data[122]
  PIN rsp_data[123]
    DIRECTION OUTPUT ;
    USE SIGNAL ;
    PORT
      LAYER metal10 ;
        RECT  503.095 839.07 505.095 841.07 ;
    END
  END rsp_data[123]
  PIN rsp_data[124]
    DIRECTION OUTPUT ;
    USE SIGNAL ;
    PORT
      LAYER metal10 ;
        RECT  511.095 839.07 513.095 841.07 ;
    END
  END rsp_data[124]
  PIN rsp_data[125]
    DIRECTION OUTPUT ;
    USE SIGNAL ;
    PORT
      LAYER metal10 ;
        RECT  519.095 839.07 521.095 841.07 ;
    END
  END rsp_data[125]
  PIN rsp_data[126]
    DIRECTION OUTPUT ;
    USE SIGNAL ;
    PORT
      LAYER metal10 ;
        RECT  527.095 839.07 529.095 841.07 ;
    END
  END rsp_data[126]
  PIN rsp_data[127]
    DIRECTION OUTPUT ;
    USE SIGNAL ;
    PORT
      LAYER metal10 ;
        RECT  535.095 839.07 537.095 841.07 ;
    END
  END rsp_data[127]
  PIN rsp_data[12]
    DIRECTION OUTPUT ;
    USE SIGNAL ;
    PORT
      LAYER metal10 ;
        RECT  127.095 415.07 129.095 417.07 ;
    END
  END rsp_data[12]
  PIN rsp_data[13]
    DIRECTION OUTPUT ;
    USE SIGNAL ;
    PORT
      LAYER metal10 ;
        RECT  135.095 415.07 137.095 417.07 ;
    END
  END rsp_data[13]
  PIN rsp_data[14]
    DIRECTION OUTPUT ;
    USE SIGNAL ;
    PORT
      LAYER metal10 ;
        RECT  143.095 415.07 145.095 417.07 ;
    END
  END rsp_data[14]
  PIN rsp_data[15]
    DIRECTION OUTPUT ;
    USE SIGNAL ;
    PORT
      LAYER metal10 ;
        RECT  151.095 415.07 153.095 417.07 ;
    END
  END rsp_data[15]
  PIN rsp_data[16]
    DIRECTION OUTPUT ;
    USE SIGNAL ;
    PORT
      LAYER metal10 ;
        RECT  31.095 839.07 33.095 841.07 ;
    END
  END rsp_data[16]
  PIN rsp_data[17]
    DIRECTION OUTPUT ;
    USE SIGNAL ;
    PORT
      LAYER metal10 ;
        RECT  39.095 839.07 41.095 841.07 ;
    END
  END rsp_data[17]
  PIN rsp_data[18]
    DIRECTION OUTPUT ;
    USE SIGNAL ;
    PORT
      LAYER metal10 ;
        RECT  47.095 839.07 49.095 841.07 ;
    END
  END rsp_data[18]
  PIN rsp_data[19]
    DIRECTION OUTPUT ;
    USE SIGNAL ;
    PORT
      LAYER metal10 ;
        RECT  55.095 839.07 57.095 841.07 ;
    END
  END rsp_data[19]
  PIN rsp_data[1]
    DIRECTION OUTPUT ;
    USE SIGNAL ;
    PORT
      LAYER metal10 ;
        RECT  39.095 415.07 41.095 417.07 ;
    END
  END rsp_data[1]
  PIN rsp_data[20]
    DIRECTION OUTPUT ;
    USE SIGNAL ;
    PORT
      LAYER metal10 ;
        RECT  63.095 839.07 65.095 841.07 ;
    END
  END rsp_data[20]
  PIN rsp_data[21]
    DIRECTION OUTPUT ;
    USE SIGNAL ;
    PORT
      LAYER metal10 ;
        RECT  71.095 839.07 73.095 841.07 ;
    END
  END rsp_data[21]
  PIN rsp_data[22]
    DIRECTION OUTPUT ;
    USE SIGNAL ;
    PORT
      LAYER metal10 ;
        RECT  79.095 839.07 81.095 841.07 ;
    END
  END rsp_data[22]
  PIN rsp_data[23]
    DIRECTION OUTPUT ;
    USE SIGNAL ;
    PORT
      LAYER metal10 ;
        RECT  87.095 839.07 89.095 841.07 ;
    END
  END rsp_data[23]
  PIN rsp_data[24]
    DIRECTION OUTPUT ;
    USE SIGNAL ;
    PORT
      LAYER metal10 ;
        RECT  95.095 839.07 97.095 841.07 ;
    END
  END rsp_data[24]
  PIN rsp_data[25]
    DIRECTION OUTPUT ;
    USE SIGNAL ;
    PORT
      LAYER metal10 ;
        RECT  103.095 839.07 105.095 841.07 ;
    END
  END rsp_data[25]
  PIN rsp_data[26]
    DIRECTION OUTPUT ;
    USE SIGNAL ;
    PORT
      LAYER metal10 ;
        RECT  111.095 839.07 113.095 841.07 ;
    END
  END rsp_data[26]
  PIN rsp_data[27]
    DIRECTION OUTPUT ;
    USE SIGNAL ;
    PORT
      LAYER metal10 ;
        RECT  119.095 839.07 121.095 841.07 ;
    END
  END rsp_data[27]
  PIN rsp_data[28]
    DIRECTION OUTPUT ;
    USE SIGNAL ;
    PORT
      LAYER metal10 ;
        RECT  127.095 839.07 129.095 841.07 ;
    END
  END rsp_data[28]
  PIN rsp_data[29]
    DIRECTION OUTPUT ;
    USE SIGNAL ;
    PORT
      LAYER metal10 ;
        RECT  135.095 839.07 137.095 841.07 ;
    END
  END rsp_data[29]
  PIN rsp_data[2]
    DIRECTION OUTPUT ;
    USE SIGNAL ;
    PORT
      LAYER metal10 ;
        RECT  47.095 415.07 49.095 417.07 ;
    END
  END rsp_data[2]
  PIN rsp_data[30]
    DIRECTION OUTPUT ;
    USE SIGNAL ;
    PORT
      LAYER metal10 ;
        RECT  143.095 839.07 145.095 841.07 ;
    END
  END rsp_data[30]
  PIN rsp_data[31]
    DIRECTION OUTPUT ;
    USE SIGNAL ;
    PORT
      LAYER metal10 ;
        RECT  151.095 839.07 153.095 841.07 ;
    END
  END rsp_data[31]
  PIN rsp_data[32]
    DIRECTION OUTPUT ;
    USE SIGNAL ;
    PORT
      LAYER metal10 ;
        RECT  159.095 415.07 161.095 417.07 ;
    END
  END rsp_data[32]
  PIN rsp_data[33]
    DIRECTION OUTPUT ;
    USE SIGNAL ;
    PORT
      LAYER metal10 ;
        RECT  167.095 415.07 169.095 417.07 ;
    END
  END rsp_data[33]
  PIN rsp_data[34]
    DIRECTION OUTPUT ;
    USE SIGNAL ;
    PORT
      LAYER metal10 ;
        RECT  175.095 415.07 177.095 417.07 ;
    END
  END rsp_data[34]
  PIN rsp_data[35]
    DIRECTION OUTPUT ;
    USE SIGNAL ;
    PORT
      LAYER metal10 ;
        RECT  183.095 415.07 185.095 417.07 ;
    END
  END rsp_data[35]
  PIN rsp_data[36]
    DIRECTION OUTPUT ;
    USE SIGNAL ;
    PORT
      LAYER metal10 ;
        RECT  191.095 415.07 193.095 417.07 ;
    END
  END rsp_data[36]
  PIN rsp_data[37]
    DIRECTION OUTPUT ;
    USE SIGNAL ;
    PORT
      LAYER metal10 ;
        RECT  199.095 415.07 201.095 417.07 ;
    END
  END rsp_data[37]
  PIN rsp_data[38]
    DIRECTION OUTPUT ;
    USE SIGNAL ;
    PORT
      LAYER metal10 ;
        RECT  207.095 415.07 209.095 417.07 ;
    END
  END rsp_data[38]
  PIN rsp_data[39]
    DIRECTION OUTPUT ;
    USE SIGNAL ;
    PORT
      LAYER metal10 ;
        RECT  215.095 415.07 217.095 417.07 ;
    END
  END rsp_data[39]
  PIN rsp_data[3]
    DIRECTION OUTPUT ;
    USE SIGNAL ;
    PORT
      LAYER metal10 ;
        RECT  55.095 415.07 57.095 417.07 ;
    END
  END rsp_data[3]
  PIN rsp_data[40]
    DIRECTION OUTPUT ;
    USE SIGNAL ;
    PORT
      LAYER metal10 ;
        RECT  223.095 415.07 225.095 417.07 ;
    END
  END rsp_data[40]
  PIN rsp_data[41]
    DIRECTION OUTPUT ;
    USE SIGNAL ;
    PORT
      LAYER metal10 ;
        RECT  231.095 415.07 233.095 417.07 ;
    END
  END rsp_data[41]
  PIN rsp_data[42]
    DIRECTION OUTPUT ;
    USE SIGNAL ;
    PORT
      LAYER metal10 ;
        RECT  239.095 415.07 241.095 417.07 ;
    END
  END rsp_data[42]
  PIN rsp_data[43]
    DIRECTION OUTPUT ;
    USE SIGNAL ;
    PORT
      LAYER metal10 ;
        RECT  247.095 415.07 249.095 417.07 ;
    END
  END rsp_data[43]
  PIN rsp_data[44]
    DIRECTION OUTPUT ;
    USE SIGNAL ;
    PORT
      LAYER metal10 ;
        RECT  255.095 415.07 257.095 417.07 ;
    END
  END rsp_data[44]
  PIN rsp_data[45]
    DIRECTION OUTPUT ;
    USE SIGNAL ;
    PORT
      LAYER metal10 ;
        RECT  263.095 415.07 265.095 417.07 ;
    END
  END rsp_data[45]
  PIN rsp_data[46]
    DIRECTION OUTPUT ;
    USE SIGNAL ;
    PORT
      LAYER metal10 ;
        RECT  271.095 415.07 273.095 417.07 ;
    END
  END rsp_data[46]
  PIN rsp_data[47]
    DIRECTION OUTPUT ;
    USE SIGNAL ;
    PORT
      LAYER metal10 ;
        RECT  279.095 415.07 281.095 417.07 ;
    END
  END rsp_data[47]
  PIN rsp_data[48]
    DIRECTION OUTPUT ;
    USE SIGNAL ;
    PORT
      LAYER metal10 ;
        RECT  159.095 839.07 161.095 841.07 ;
    END
  END rsp_data[48]
  PIN rsp_data[49]
    DIRECTION OUTPUT ;
    USE SIGNAL ;
    PORT
      LAYER metal10 ;
        RECT  167.095 839.07 169.095 841.07 ;
    END
  END rsp_data[49]
  PIN rsp_data[4]
    DIRECTION OUTPUT ;
    USE SIGNAL ;
    PORT
      LAYER metal10 ;
        RECT  63.095 415.07 65.095 417.07 ;
    END
  END rsp_data[4]
  PIN rsp_data[50]
    DIRECTION OUTPUT ;
    USE SIGNAL ;
    PORT
      LAYER metal10 ;
        RECT  175.095 839.07 177.095 841.07 ;
    END
  END rsp_data[50]
  PIN rsp_data[51]
    DIRECTION OUTPUT ;
    USE SIGNAL ;
    PORT
      LAYER metal10 ;
        RECT  183.095 839.07 185.095 841.07 ;
    END
  END rsp_data[51]
  PIN rsp_data[52]
    DIRECTION OUTPUT ;
    USE SIGNAL ;
    PORT
      LAYER metal10 ;
        RECT  191.095 839.07 193.095 841.07 ;
    END
  END rsp_data[52]
  PIN rsp_data[53]
    DIRECTION OUTPUT ;
    USE SIGNAL ;
    PORT
      LAYER metal10 ;
        RECT  199.095 839.07 201.095 841.07 ;
    END
  END rsp_data[53]
  PIN rsp_data[54]
    DIRECTION OUTPUT ;
    USE SIGNAL ;
    PORT
      LAYER metal10 ;
        RECT  207.095 839.07 209.095 841.07 ;
    END
  END rsp_data[54]
  PIN rsp_data[55]
    DIRECTION OUTPUT ;
    USE SIGNAL ;
    PORT
      LAYER metal10 ;
        RECT  215.095 839.07 217.095 841.07 ;
    END
  END rsp_data[55]
  PIN rsp_data[56]
    DIRECTION OUTPUT ;
    USE SIGNAL ;
    PORT
      LAYER metal10 ;
        RECT  223.095 839.07 225.095 841.07 ;
    END
  END rsp_data[56]
  PIN rsp_data[57]
    DIRECTION OUTPUT ;
    USE SIGNAL ;
    PORT
      LAYER metal10 ;
        RECT  231.095 839.07 233.095 841.07 ;
    END
  END rsp_data[57]
  PIN rsp_data[58]
    DIRECTION OUTPUT ;
    USE SIGNAL ;
    PORT
      LAYER metal10 ;
        RECT  239.095 839.07 241.095 841.07 ;
    END
  END rsp_data[58]
  PIN rsp_data[59]
    DIRECTION OUTPUT ;
    USE SIGNAL ;
    PORT
      LAYER metal10 ;
        RECT  247.095 839.07 249.095 841.07 ;
    END
  END rsp_data[59]
  PIN rsp_data[5]
    DIRECTION OUTPUT ;
    USE SIGNAL ;
    PORT
      LAYER metal10 ;
        RECT  71.095 415.07 73.095 417.07 ;
    END
  END rsp_data[5]
  PIN rsp_data[60]
    DIRECTION OUTPUT ;
    USE SIGNAL ;
    PORT
      LAYER metal10 ;
        RECT  255.095 839.07 257.095 841.07 ;
    END
  END rsp_data[60]
  PIN rsp_data[61]
    DIRECTION OUTPUT ;
    USE SIGNAL ;
    PORT
      LAYER metal10 ;
        RECT  263.095 839.07 265.095 841.07 ;
    END
  END rsp_data[61]
  PIN rsp_data[62]
    DIRECTION OUTPUT ;
    USE SIGNAL ;
    PORT
      LAYER metal10 ;
        RECT  271.095 839.07 273.095 841.07 ;
    END
  END rsp_data[62]
  PIN rsp_data[63]
    DIRECTION OUTPUT ;
    USE SIGNAL ;
    PORT
      LAYER metal10 ;
        RECT  279.095 839.07 281.095 841.07 ;
    END
  END rsp_data[63]
  PIN rsp_data[64]
    DIRECTION OUTPUT ;
    USE SIGNAL ;
    PORT
      LAYER metal10 ;
        RECT  287.095 415.07 289.095 417.07 ;
    END
  END rsp_data[64]
  PIN rsp_data[65]
    DIRECTION OUTPUT ;
    USE SIGNAL ;
    PORT
      LAYER metal10 ;
        RECT  295.095 415.07 297.095 417.07 ;
    END
  END rsp_data[65]
  PIN rsp_data[66]
    DIRECTION OUTPUT ;
    USE SIGNAL ;
    PORT
      LAYER metal10 ;
        RECT  303.095 415.07 305.095 417.07 ;
    END
  END rsp_data[66]
  PIN rsp_data[67]
    DIRECTION OUTPUT ;
    USE SIGNAL ;
    PORT
      LAYER metal10 ;
        RECT  311.095 415.07 313.095 417.07 ;
    END
  END rsp_data[67]
  PIN rsp_data[68]
    DIRECTION OUTPUT ;
    USE SIGNAL ;
    PORT
      LAYER metal10 ;
        RECT  319.095 415.07 321.095 417.07 ;
    END
  END rsp_data[68]
  PIN rsp_data[69]
    DIRECTION OUTPUT ;
    USE SIGNAL ;
    PORT
      LAYER metal10 ;
        RECT  327.095 415.07 329.095 417.07 ;
    END
  END rsp_data[69]
  PIN rsp_data[6]
    DIRECTION OUTPUT ;
    USE SIGNAL ;
    PORT
      LAYER metal10 ;
        RECT  79.095 415.07 81.095 417.07 ;
    END
  END rsp_data[6]
  PIN rsp_data[70]
    DIRECTION OUTPUT ;
    USE SIGNAL ;
    PORT
      LAYER metal10 ;
        RECT  335.095 415.07 337.095 417.07 ;
    END
  END rsp_data[70]
  PIN rsp_data[71]
    DIRECTION OUTPUT ;
    USE SIGNAL ;
    PORT
      LAYER metal10 ;
        RECT  343.095 415.07 345.095 417.07 ;
    END
  END rsp_data[71]
  PIN rsp_data[72]
    DIRECTION OUTPUT ;
    USE SIGNAL ;
    PORT
      LAYER metal10 ;
        RECT  351.095 415.07 353.095 417.07 ;
    END
  END rsp_data[72]
  PIN rsp_data[73]
    DIRECTION OUTPUT ;
    USE SIGNAL ;
    PORT
      LAYER metal10 ;
        RECT  359.095 415.07 361.095 417.07 ;
    END
  END rsp_data[73]
  PIN rsp_data[74]
    DIRECTION OUTPUT ;
    USE SIGNAL ;
    PORT
      LAYER metal10 ;
        RECT  367.095 415.07 369.095 417.07 ;
    END
  END rsp_data[74]
  PIN rsp_data[75]
    DIRECTION OUTPUT ;
    USE SIGNAL ;
    PORT
      LAYER metal10 ;
        RECT  375.095 415.07 377.095 417.07 ;
    END
  END rsp_data[75]
  PIN rsp_data[76]
    DIRECTION OUTPUT ;
    USE SIGNAL ;
    PORT
      LAYER metal10 ;
        RECT  383.095 415.07 385.095 417.07 ;
    END
  END rsp_data[76]
  PIN rsp_data[77]
    DIRECTION OUTPUT ;
    USE SIGNAL ;
    PORT
      LAYER metal10 ;
        RECT  391.095 415.07 393.095 417.07 ;
    END
  END rsp_data[77]
  PIN rsp_data[78]
    DIRECTION OUTPUT ;
    USE SIGNAL ;
    PORT
      LAYER metal10 ;
        RECT  399.095 415.07 401.095 417.07 ;
    END
  END rsp_data[78]
  PIN rsp_data[79]
    DIRECTION OUTPUT ;
    USE SIGNAL ;
    PORT
      LAYER metal10 ;
        RECT  407.095 415.07 409.095 417.07 ;
    END
  END rsp_data[79]
  PIN rsp_data[7]
    DIRECTION OUTPUT ;
    USE SIGNAL ;
    PORT
      LAYER metal10 ;
        RECT  87.095 415.07 89.095 417.07 ;
    END
  END rsp_data[7]
  PIN rsp_data[80]
    DIRECTION OUTPUT ;
    USE SIGNAL ;
    PORT
      LAYER metal10 ;
        RECT  287.095 839.07 289.095 841.07 ;
    END
  END rsp_data[80]
  PIN rsp_data[81]
    DIRECTION OUTPUT ;
    USE SIGNAL ;
    PORT
      LAYER metal10 ;
        RECT  295.095 839.07 297.095 841.07 ;
    END
  END rsp_data[81]
  PIN rsp_data[82]
    DIRECTION OUTPUT ;
    USE SIGNAL ;
    PORT
      LAYER metal10 ;
        RECT  303.095 839.07 305.095 841.07 ;
    END
  END rsp_data[82]
  PIN rsp_data[83]
    DIRECTION OUTPUT ;
    USE SIGNAL ;
    PORT
      LAYER metal10 ;
        RECT  311.095 839.07 313.095 841.07 ;
    END
  END rsp_data[83]
  PIN rsp_data[84]
    DIRECTION OUTPUT ;
    USE SIGNAL ;
    PORT
      LAYER metal10 ;
        RECT  319.095 839.07 321.095 841.07 ;
    END
  END rsp_data[84]
  PIN rsp_data[85]
    DIRECTION OUTPUT ;
    USE SIGNAL ;
    PORT
      LAYER metal10 ;
        RECT  327.095 839.07 329.095 841.07 ;
    END
  END rsp_data[85]
  PIN rsp_data[86]
    DIRECTION OUTPUT ;
    USE SIGNAL ;
    PORT
      LAYER metal10 ;
        RECT  335.095 839.07 337.095 841.07 ;
    END
  END rsp_data[86]
  PIN rsp_data[87]
    DIRECTION OUTPUT ;
    USE SIGNAL ;
    PORT
      LAYER metal10 ;
        RECT  343.095 839.07 345.095 841.07 ;
    END
  END rsp_data[87]
  PIN rsp_data[88]
    DIRECTION OUTPUT ;
    USE SIGNAL ;
    PORT
      LAYER metal10 ;
        RECT  351.095 839.07 353.095 841.07 ;
    END
  END rsp_data[88]
  PIN rsp_data[89]
    DIRECTION OUTPUT ;
    USE SIGNAL ;
    PORT
      LAYER metal10 ;
        RECT  359.095 839.07 361.095 841.07 ;
    END
  END rsp_data[89]
  PIN rsp_data[8]
    DIRECTION OUTPUT ;
    USE SIGNAL ;
    PORT
      LAYER metal10 ;
        RECT  95.095 415.07 97.095 417.07 ;
    END
  END rsp_data[8]
  PIN rsp_data[90]
    DIRECTION OUTPUT ;
    USE SIGNAL ;
    PORT
      LAYER metal10 ;
        RECT  367.095 839.07 369.095 841.07 ;
    END
  END rsp_data[90]
  PIN rsp_data[91]
    DIRECTION OUTPUT ;
    USE SIGNAL ;
    PORT
      LAYER metal10 ;
        RECT  375.095 839.07 377.095 841.07 ;
    END
  END rsp_data[91]
  PIN rsp_data[92]
    DIRECTION OUTPUT ;
    USE SIGNAL ;
    PORT
      LAYER metal10 ;
        RECT  383.095 839.07 385.095 841.07 ;
    END
  END rsp_data[92]
  PIN rsp_data[93]
    DIRECTION OUTPUT ;
    USE SIGNAL ;
    PORT
      LAYER metal10 ;
        RECT  391.095 839.07 393.095 841.07 ;
    END
  END rsp_data[93]
  PIN rsp_data[94]
    DIRECTION OUTPUT ;
    USE SIGNAL ;
    PORT
      LAYER metal10 ;
        RECT  399.095 839.07 401.095 841.07 ;
    END
  END rsp_data[94]
  PIN rsp_data[95]
    DIRECTION OUTPUT ;
    USE SIGNAL ;
    PORT
      LAYER metal10 ;
        RECT  407.095 839.07 409.095 841.07 ;
    END
  END rsp_data[95]
  PIN rsp_data[96]
    DIRECTION OUTPUT ;
    USE SIGNAL ;
    PORT
      LAYER metal10 ;
        RECT  415.095 415.07 417.095 417.07 ;
    END
  END rsp_data[96]
  PIN rsp_data[97]
    DIRECTION OUTPUT ;
    USE SIGNAL ;
    PORT
      LAYER metal10 ;
        RECT  423.095 415.07 425.095 417.07 ;
    END
  END rsp_data[97]
  PIN rsp_data[98]
    DIRECTION OUTPUT ;
    USE SIGNAL ;
    PORT
      LAYER metal10 ;
        RECT  431.095 415.07 433.095 417.07 ;
    END
  END rsp_data[98]
  PIN rsp_data[99]
    DIRECTION OUTPUT ;
    USE SIGNAL ;
    PORT
      LAYER metal10 ;
        RECT  439.095 415.07 441.095 417.07 ;
    END
  END rsp_data[99]
  PIN rsp_data[9]
    DIRECTION OUTPUT ;
    USE SIGNAL ;
    PORT
      LAYER metal10 ;
        RECT  103.095 415.07 105.095 417.07 ;
    END
  END rsp_data[9]
  PIN rsp_error
    DIRECTION OUTPUT ;
    USE SIGNAL ;
    PORT
      LAYER metal10 ;
        RECT  543.095 415.07 545.095 417.07 ;
    END
  END rsp_error
  PIN rsp_ready
    DIRECTION INPUT ;
    USE SIGNAL ;
    PORT
      LAYER metal10 ;
        RECT  839.095 615.07 841.095 617.07 ;
    END
  END rsp_ready
  PIN rsp_saturated
    DIRECTION OUTPUT ;
    USE SIGNAL ;
    PORT
      LAYER metal10 ;
        RECT  543.095 839.07 545.095 841.07 ;
    END
  END rsp_saturated
  PIN rsp_valid
    DIRECTION OUTPUT ;
    USE SIGNAL ;
    PORT
      LAYER metal10 ;
        RECT  551.095 415.07 553.095 417.07 ;
    END
  END rsp_valid
  PIN VSS
    DIRECTION INOUT ;
    USE GROUND ;
    PORT
      LAYER metal7 ;
        RECT  20.14 1222.3 1239.94 1223.7 ;
        RECT  20.14 1192.3 1239.94 1193.7 ;
        RECT  20.14 1162.3 1239.94 1163.7 ;
        RECT  20.14 1132.3 1239.94 1133.7 ;
        RECT  20.14 1102.3 1239.94 1103.7 ;
        RECT  20.14 1072.3 1239.94 1073.7 ;
        RECT  20.14 1042.3 1239.94 1043.7 ;
        RECT  20.14 1012.3 1239.94 1013.7 ;
        RECT  20.14 982.3 1239.94 983.7 ;
        RECT  20.14 952.3 1239.94 953.7 ;
        RECT  20.14 922.3 1239.94 923.7 ;
        RECT  20.14 892.3 1239.94 893.7 ;
        RECT  20.14 862.3 1239.94 863.7 ;
        RECT  20.14 832.3 1239.94 833.7 ;
        RECT  20.14 802.3 1239.94 803.7 ;
        RECT  20.14 772.3 1239.94 773.7 ;
        RECT  20.14 742.3 1239.94 743.7 ;
        RECT  20.14 712.3 1239.94 713.7 ;
        RECT  20.14 682.3 1239.94 683.7 ;
        RECT  20.14 652.3 1239.94 653.7 ;
        RECT  20.14 622.3 1239.94 623.7 ;
        RECT  20.14 592.3 1239.94 593.7 ;
        RECT  20.14 562.3 1239.94 563.7 ;
        RECT  20.14 532.3 1239.94 533.7 ;
        RECT  20.14 502.3 1239.94 503.7 ;
        RECT  20.14 472.3 1239.94 473.7 ;
        RECT  20.14 442.3 1239.94 443.7 ;
        RECT  20.14 412.3 1239.94 413.7 ;
        RECT  20.14 382.3 1239.94 383.7 ;
        RECT  20.14 352.3 1239.94 353.7 ;
        RECT  20.14 322.3 1239.94 323.7 ;
        RECT  20.14 292.3 1239.94 293.7 ;
        RECT  20.14 262.3 1239.94 263.7 ;
        RECT  20.14 232.3 1239.94 233.7 ;
        RECT  20.14 202.3 1239.94 203.7 ;
        RECT  20.14 172.3 1239.94 173.7 ;
        RECT  20.14 142.3 1239.94 143.7 ;
        RECT  20.14 112.3 1239.94 113.7 ;
        RECT  20.14 82.3 1239.94 83.7 ;
        RECT  20.14 52.3 1239.94 53.7 ;
        RECT  20.14 22.3 1239.94 23.7 ;
    END
  END VSS
  PIN VDD
    DIRECTION INOUT ;
    USE POWER ;
    PORT
      LAYER metal7 ;
        RECT  20.14 1237.3 1239.94 1238.7 ;
        RECT  20.14 1207.3 1239.94 1208.7 ;
        RECT  20.14 1177.3 1239.94 1178.7 ;
        RECT  20.14 1147.3 1239.94 1148.7 ;
        RECT  20.14 1117.3 1239.94 1118.7 ;
        RECT  20.14 1087.3 1239.94 1088.7 ;
        RECT  20.14 1057.3 1239.94 1058.7 ;
        RECT  20.14 1027.3 1239.94 1028.7 ;
        RECT  20.14 997.3 1239.94 998.7 ;
        RECT  20.14 967.3 1239.94 968.7 ;
        RECT  20.14 937.3 1239.94 938.7 ;
        RECT  20.14 907.3 1239.94 908.7 ;
        RECT  20.14 877.3 1239.94 878.7 ;
        RECT  20.14 847.3 1239.94 848.7 ;
        RECT  20.14 817.3 1239.94 818.7 ;
        RECT  20.14 787.3 1239.94 788.7 ;
        RECT  20.14 757.3 1239.94 758.7 ;
        RECT  20.14 727.3 1239.94 728.7 ;
        RECT  20.14 697.3 1239.94 698.7 ;
        RECT  20.14 667.3 1239.94 668.7 ;
        RECT  20.14 637.3 1239.94 638.7 ;
        RECT  20.14 607.3 1239.94 608.7 ;
        RECT  20.14 577.3 1239.94 578.7 ;
        RECT  20.14 547.3 1239.94 548.7 ;
        RECT  20.14 517.3 1239.94 518.7 ;
        RECT  20.14 487.3 1239.94 488.7 ;
        RECT  20.14 457.3 1239.94 458.7 ;
        RECT  20.14 427.3 1239.94 428.7 ;
        RECT  20.14 397.3 1239.94 398.7 ;
        RECT  20.14 367.3 1239.94 368.7 ;
        RECT  20.14 337.3 1239.94 338.7 ;
        RECT  20.14 307.3 1239.94 308.7 ;
        RECT  20.14 277.3 1239.94 278.7 ;
        RECT  20.14 247.3 1239.94 248.7 ;
        RECT  20.14 217.3 1239.94 218.7 ;
        RECT  20.14 187.3 1239.94 188.7 ;
        RECT  20.14 157.3 1239.94 158.7 ;
        RECT  20.14 127.3 1239.94 128.7 ;
        RECT  20.14 97.3 1239.94 98.7 ;
        RECT  20.14 67.3 1239.94 68.7 ;
        RECT  20.14 37.3 1239.94 38.7 ;
    END
  END VDD
  OBS
    LAYER metal1 ;
     RECT  19.345 14.84 1259.325 1251.46 ;
    LAYER metal2 ;
     RECT  19.345 14.84 1259.325 1251.46 ;
    LAYER metal3 ;
     RECT  19.345 14.84 1259.325 1251.46 ;
    LAYER metal4 ;
     RECT  19.345 14.84 1259.325 1251.46 ;
    LAYER metal5 ;
     RECT  19.345 14.84 1259.325 1251.46 ;
    LAYER metal6 ;
     RECT  19.345 14.84 1259.325 1251.46 ;
    LAYER metal7 ;
     RECT  19.345 14.84 1259.325 1251.46 ;
    LAYER metal8 ;
     RECT  19.345 14.84 1259.325 1251.46 ;
    LAYER metal9 ;
     RECT  19.345 14.84 1259.325 1251.46 ;
    LAYER metal10 ;
     RECT  19.345 14.84 1259.325 1251.46 ;
  END
END block_v1_v
END LIBRARY
